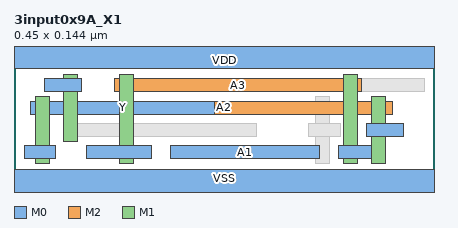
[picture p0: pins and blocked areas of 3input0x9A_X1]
MACRO 3input0x9A_X1
  CLASS CORE ;
  ORIGIN 0 0 ;
  FOREIGN 3input0x9A_X1 0 0 ;
  SIZE 0.4500 BY 0.1440 ;
  SYMMETRY X Y ;
  SITE coresite ;
  PIN A1
    DIRECTION INPUT ;
    USE SIGNAL ;
    PORT
      LAYER M0 ;
        RECT 0.1680 0.0290 0.3270 0.0430 ;
    END
  END A1
  PIN A2
    DIRECTION INPUT ;
    USE SIGNAL ;
    PORT
      LAYER M2 ;
        RECT 0.0450 0.0770 0.4050 0.0910 ;
      LAYER M1 ;
        RECT 0.0530 0.0480 0.0680 0.1200 ;
        RECT 0.3830 0.0240 0.3980 0.0960 ;
      LAYER M0 ;
        RECT 0.3780 0.0530 0.4170 0.0670 ;
        RECT 0.0330 0.1010 0.0720 0.1150 ;
    END
  END A2
  PIN A3
    DIRECTION INPUT ;
    USE SIGNAL ;
    PORT
      LAYER M2 ;
        RECT 0.1080 0.1010 0.3720 0.1150 ;
      LAYER M1 ;
        RECT 0.1130 0.0240 0.1280 0.1200 ;
        RECT 0.3530 0.0240 0.3680 0.1200 ;
      LAYER M0 ;
        RECT 0.3480 0.0290 0.3830 0.0430 ;
        RECT 0.0780 0.0290 0.1470 0.0430 ;
    END
  END A3
  PIN Y
    DIRECTION OUTPUT ;
    USE SIGNAL ;
    PORT
      LAYER M1 ;
        RECT 0.0230 0.0240 0.0380 0.0960 ;
      LAYER M0 ;
        RECT 0.0180 0.0770 0.2150 0.0910 ;
        RECT 0.0110 0.0290 0.0450 0.0430 ;
    END
  END Y
  PIN VDD
    DIRECTION INOUT ;
    USE POWER ;
    SHAPE ABUTMENT ;
    PORT
      LAYER M0 ;
        RECT 0.0000 0.1260 0.4500 0.1620 ;
    END
  END VDD
  PIN VSS
    DIRECTION INOUT ;
    USE GROUND ;
    SHAPE ABUTMENT ;
    PORT
      LAYER M0 ;
        RECT 0.0000 -0.0180 0.4500 0.0180 ;
    END
  END VSS
  OBS
    LAYER V1 ;
      RECT 0.0530 0.0770 0.0670 0.0910 ;
      RECT 0.3830 0.0770 0.3970 0.0910 ;
      RECT 0.1130 0.1010 0.1270 0.1150 ;
      RECT 0.3530 0.1010 0.3670 0.1150 ;
    LAYER M1 ;
      RECT 0.3230 0.0240 0.3380 0.0960 ;
    LAYER V0 ;
      RECT 0.0530 0.1010 0.0670 0.1150 ;
      RECT 0.3830 0.0530 0.3970 0.0670 ;
      RECT 0.3230 0.0770 0.3370 0.0910 ;
      RECT 0.3230 0.0530 0.3370 0.0670 ;
      RECT 0.1130 0.0290 0.1270 0.0430 ;
      RECT 0.3530 0.0290 0.3670 0.0430 ;
      RECT 0.0230 0.0770 0.0370 0.0910 ;
      RECT 0.0230 0.0290 0.0370 0.0430 ;
    LAYER M0 ;
      RECT 0.0560 0.0530 0.2600 0.0670 ;
      RECT 0.3150 0.0530 0.3500 0.0670 ;
      RECT 0.2580 0.0770 0.3950 0.0910 ;
      RECT 0.1460 0.1010 0.2600 0.1150 ;
      RECT 0.3260 0.1010 0.4400 0.1150 ;
  END
END 3input0x9A_X1
